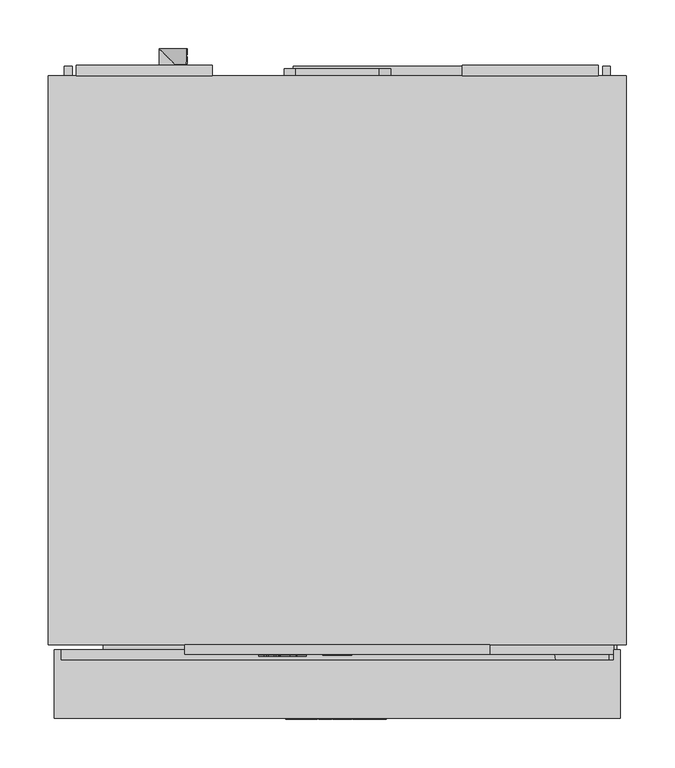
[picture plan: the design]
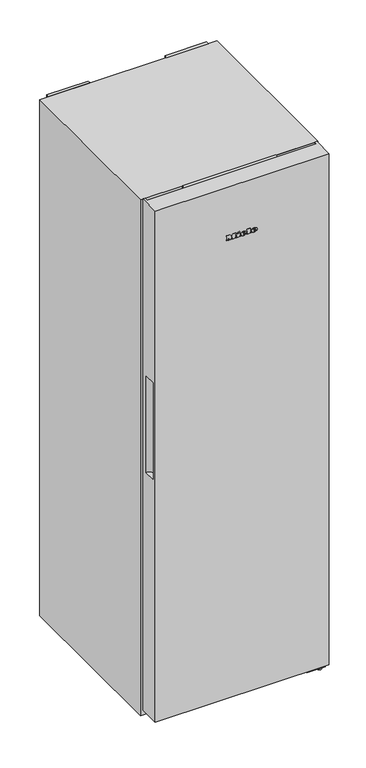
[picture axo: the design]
"""IFC4 building model written with IfcOpenShell, lengths in millimetres: proxy geometry."""

from ifc_helpers import new_model, si_unit, point, frame, frame_2d, origin, origin_with_axes, place, context, project, spatial, polyline, circle_curve, ellipse_curve, trimmed, segment, composite_curve, outline, extrude, faceted_brep, source, transform, mapped, element, save
from ifc_brep_helpers import plane_surface, cylinder_surface, revolved_surface, extruded_surface, advanced_brep


def specialty_equipment_c88ea4fe(model_context):
    return source(origin(), model_context, "Body", "SolidModel", [
        extrude(outline(polyline([(15.0, -609.5), (-15.0, -609.5), (-15.0, -606.5), (15.0, -606.5), (15.0, -609.5)])), frame((0.0, 0.0, 1812.0), z_axis=(0.0, 0.0, 1.0), x_axis=(1.0, 0.0, 0.0)), (0.0, 0.0, 1.0), 28.0),
        extrude(outline(polyline([(1845.5, 105.0), (1845.5, -105.0), (1806.5, -105.0), (1806.5, 105.0), (1845.5, 105.0)]), holes=[polyline([(1840.0, -15.0), (1840.0, 15.0), (1812.0, 15.0), (1812.0, -15.0), (1840.0, -15.0)])]), frame((0.0, -608.5, 0.0), z_axis=(0.0, 1.0, 0.0), x_axis=(0.0, 0.0, 1.0)), (0.0, 0.0, 1.0), 2.0),
        faceted_brep([(157.5, -598.5, 1802.0), (157.5, -608.5, 1802.0), (-157.5, -608.5, 1802.0), (-157.5, -598.5, 1802.0), (157.5, -598.5, 1850.0), (-157.5, -598.5, 1850.0), (-157.5, -608.5, 1850.0), (157.5, -608.5, 1850.0), (-105.0, -608.5, 1845.5), (105.0, -608.5, 1845.5), (105.0, -608.5, 1806.5), (-105.0, -608.5, 1806.5), (105.0, -606.5, 1845.5), (-105.0, -606.5, 1845.5), (-105.0, -606.5, 1806.5), (105.0, -606.5, 1806.5)], [[[0, 1, 2, 3]], [[4, 5, 6, 7]], [[0, 3, 5, 4]], [[3, 2, 6, 5]], [[2, 1, 7, 6], [8, 9, 10, 11]], [[1, 0, 4, 7]], [[12, 13, 14, 15]], [[13, 12, 9, 8]], [[14, 13, 8, 11]], [[15, 14, 11, 10]], [[12, 15, 10, 9]]]),
        advanced_brep(
        [(39.0804776, -675.5, 1668.7956125), (39.0804776, -675.5, 1670.5126125), (50.4534776, -675.5, 1670.5126125), (30.6654776, -675.5, 1670.5126125), (35.3404776, -675.5, 1664.7666125), (50.1644776, -675.5, 1668.7956125), (45.0304776, -675.5, 1668.7956125), (40.9844776, -675.5, 1666.8916125), (39.0804776, -675.5, 1672.6886125), (39.0804776, -675.5, 1674.5416125), (41.9874776, -675.5, 1674.5416125), (41.9874776, -675.5, 1672.6886125), (39.0804776, -674.5, 1668.7956125), (40.9844776, -674.5, 1666.8916125), (45.0304776, -674.5, 1668.7956125), (50.1644776, -674.5, 1668.7956125), (35.3404776, -674.5, 1664.7666125), (30.6654776, -674.5, 1670.5126125), (50.4534776, -674.5, 1670.5126125), (39.0804776, -674.5, 1670.5126125), (39.0804776, -674.5, 1672.6886125), (41.9874776, -674.5, 1672.6886125), (41.9874776, -674.5, 1674.5416125), (39.0804776, -674.5, 1674.5416125)],
        [
            (0, 1),
            (1, 2),
            (2, 3, ellipse_curve(frame((40.5594776, -675.5, 1670.5126125), z_axis=(0.0, -1.0, 0.0), x_axis=(-1.0, 0.0, 0.0)), 9.894, 8.177)),
            (3, 4, circle_curve(frame((37.2445704, -675.5, 1671.0906125), z_axis=(0.0, -1.0, 0.0), x_axis=(0.0, 0.0, -1.0)), 6.6044337)),
            (4, 5, circle_curve(frame((40.361414, -675.5, 1675.5786125), z_axis=(0.0, -1.0, 0.0), x_axis=(0.0, 0.0, -1.0)), 11.9209541)),
            (5, 6),
            (6, 7, circle_curve(frame((41.8154776, -675.5, 1670.3766125), z_axis=(0.0, 1.0, 0.0), x_axis=(0.0, 0.0, -1.0)), 3.5827065)),
            (7, 0, circle_curve(frame((40.9844776, -675.5, 1668.7956125), z_axis=(0.0, 1.0, 0.0), x_axis=(0.0, 0.0, -1.0)), 1.904)),
            (8, 9),
            (9, 10, circle_curve(frame((40.5339776, -675.5, 1674.5416125), z_axis=(0.0, 1.0, 0.0), x_axis=(0.0, 0.0, -1.0)), 1.4535)),
            (10, 11),
            (11, 8),
            (12, 13, circle_curve(frame((40.9844776, -674.5, 1668.7956125), z_axis=(0.0, -1.0, 0.0), x_axis=(0.0, 0.0, -1.0)), 1.904)),
            (13, 14, circle_curve(frame((41.8154776, -674.5, 1670.3766125), z_axis=(0.0, -1.0, 0.0), x_axis=(0.0, 0.0, -1.0)), 3.5827065)),
            (14, 15),
            (15, 16, circle_curve(frame((40.361414, -674.5, 1675.5786125), z_axis=(0.0, 1.0, 0.0), x_axis=(0.0, 0.0, -1.0)), 11.9209541)),
            (16, 17, circle_curve(frame((37.2445704, -674.5, 1671.0906125), z_axis=(0.0, 1.0, 0.0), x_axis=(0.0, 0.0, -1.0)), 6.6044337)),
            (17, 18, ellipse_curve(frame((40.5594776, -674.5, 1670.5126125), z_axis=(0.0, 1.0, 0.0), x_axis=(-1.0, 0.0, 0.0)), 9.894, 8.177)),
            (18, 19),
            (19, 12),
            (20, 21),
            (21, 22),
            (22, 23, circle_curve(frame((40.5339776, -674.5, 1674.5416125), z_axis=(0.0, -1.0, 0.0), x_axis=(0.0, 0.0, -1.0)), 1.4535)),
            (23, 20),
            (0, 12),
            (19, 1),
            (18, 2),
            (5, 15),
            (14, 6),
            (17, 3),
            (13, 7),
            (16, 4),
            (8, 20),
            (23, 9),
            (22, 10),
            (21, 11),
        ],
        [
            plane_surface(frame((39.0804776, -675.5, 1670.5126125), z_axis=(0.0, -1.0, 0.0), x_axis=(0.0, 0.0, 1.0))),
            plane_surface(frame((39.0804776, -674.5, 1670.5126125), z_axis=(0.0, 1.0, 0.0), x_axis=(0.0, 0.0, -1.0))),
            plane_surface(frame((39.0804776, -675.5, 1668.7956125), z_axis=(1.0, 0.0, 0.0), x_axis=(0.0, 1.0, 0.0))),
            plane_surface(frame((39.0804776, -675.5, 1670.5126125), z_axis=(0.0, 0.0, -1.0), x_axis=(0.0, 1.0, 0.0))),
            plane_surface(frame((50.1644776, -675.5, 1668.7956125), z_axis=(0.0, 0.0, 1.0), x_axis=(0.0, 1.0, 0.0))),
            extruded_surface(trimmed(ellipse_curve(frame((40.5594776, -673.5, 1670.5126125), z_axis=(0.0, -1.0, 0.0), x_axis=(-1.0, 0.0, 0.0)), 9.894, 8.177), [point((50.4534776, -673.5, 1670.5126125))], [point((30.6654776, -673.5, 1670.5126125))], True, "CARTESIAN"), (0.0, -1.0, 0.0), 1.0),
            revolved_surface(polyline([(41.8154776, -674.5, 1666.7939059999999), (41.8154776, -675.5, 1666.7939059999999)]), (41.8154776, -674.5, 1670.3766125), (0.0, 1.0, 0.0)),
            revolved_surface(polyline([(40.9844776, -674.5, 1666.8916125), (40.9844776, -675.5, 1666.8916125)]), (40.9844776, -674.5, 1668.7956125), (0.0, 1.0, 0.0)),
            cylinder_surface(frame((37.2445704, -674.5, 1671.0906125), z_axis=(0.0, -1.0, 0.0), x_axis=(0.0, 0.0, -1.0)), 6.6044337),
            cylinder_surface(frame((40.361414, -674.5, 1675.5786125), z_axis=(0.0, -1.0, 0.0), x_axis=(0.0, 0.0, -1.0)), 11.9209541),
            plane_surface(frame((39.0804776, -675.5, 1672.6886125), z_axis=(1.0, 0.0, 0.0), x_axis=(0.0, 1.0, 0.0))),
            revolved_surface(polyline([(40.5339776, -674.5, 1673.0881124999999), (40.5339776, -675.5, 1673.0881124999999)]), (40.5339776, -674.5, 1674.5416125), (0.0, 1.0, 0.0)),
            plane_surface(frame((41.9874776, -675.5, 1674.5416125), z_axis=(-1.0, 0.0, 0.0), x_axis=(0.0, 1.0, 0.0))),
            plane_surface(frame((41.9874776, -675.5, 1672.6886125), z_axis=(0.0, 0.0, 1.0), x_axis=(0.0, 1.0, 0.0))),
        ],
        [
            (0, [[1, 2, 3, 4, 5, 6, 7, 8], [9, 10, 11, 12]]),
            (1, [[13, 14, 15, 16, 17, 18, 19, 20], [21, 22, 23, 24]]),
            (2, [[-1, 25, -20, 26]]),
            (3, [[-2, -26, -19, 27]]),
            (4, [[-6, 28, -15, 29]]),
            (5, [[-3, -27, -18, 30]]),
            (6, [[-7, -29, -14, 31]]),
            (7, [[-8, -31, -13, -25]]),
            (8, [[-4, -30, -17, 32]]),
            (9, [[-5, -32, -16, -28]]),
            (10, [[-9, 33, -24, 34]]),
            (11, [[-10, -34, -23, 35]]),
            (12, [[-11, -35, -22, 36]]),
            (13, [[-12, -36, -21, -33]]),
        ],
    ),
        advanced_brep(
        [(3.6014776, -675.5, 1668.7956125), (3.6014776, -675.5, 1670.5126125), (14.9744776, -675.5, 1670.5126125), (-4.8135224, -675.5, 1670.5126125), (-0.1385224, -675.5, 1664.7666125), (14.6854776, -675.5, 1668.7956125), (9.5514776, -675.5, 1668.7956125), (5.5054776, -675.5, 1666.8916125), (3.6014776, -675.5, 1672.6886125), (3.6014776, -675.5, 1674.5416125), (6.5084776, -675.5, 1674.5416125), (6.5084776, -675.5, 1672.6886125), (3.6014776, -674.5, 1668.7956125), (5.5054776, -674.5, 1666.8916125), (9.5514776, -674.5, 1668.7956125), (14.6854776, -674.5, 1668.7956125), (-0.1385224, -674.5, 1664.7666125), (-4.8135224, -674.5, 1670.5126125), (14.9744776, -674.5, 1670.5126125), (3.6014776, -674.5, 1670.5126125), (3.6014776, -674.5, 1672.6886125), (6.5084776, -674.5, 1672.6886125), (6.5084776, -674.5, 1674.5416125), (3.6014776, -674.5, 1674.5416125)],
        [
            (0, 1),
            (1, 2),
            (2, 3, ellipse_curve(frame((5.0804776, -675.5, 1670.5126125), z_axis=(0.0, -1.0, 0.0), x_axis=(-1.0, 0.0, 0.0)), 9.894, 8.177)),
            (3, 4, circle_curve(frame((1.7655704, -675.5, 1671.0906125), z_axis=(0.0, -1.0, 0.0), x_axis=(0.0, 0.0, -1.0)), 6.6044337)),
            (4, 5, circle_curve(frame((4.882414, -675.5, 1675.5786125), z_axis=(0.0, -1.0, 0.0), x_axis=(0.0, 0.0, -1.0)), 11.9209541)),
            (5, 6),
            (6, 7, circle_curve(frame((6.3364776, -675.5, 1670.3766125), z_axis=(0.0, 1.0, 0.0), x_axis=(0.0, 0.0, -1.0)), 3.5827065)),
            (7, 0, circle_curve(frame((5.5054776, -675.5, 1668.7956125), z_axis=(0.0, 1.0, 0.0), x_axis=(0.0, 0.0, -1.0)), 1.904)),
            (8, 9),
            (9, 10, circle_curve(frame((5.0549776, -675.5, 1674.5416125), z_axis=(0.0, 1.0, 0.0), x_axis=(0.0, 0.0, -1.0)), 1.4535)),
            (10, 11),
            (11, 8),
            (12, 13, circle_curve(frame((5.5054776, -674.5, 1668.7956125), z_axis=(0.0, -1.0, 0.0), x_axis=(0.0, 0.0, -1.0)), 1.904)),
            (13, 14, circle_curve(frame((6.3364776, -674.5, 1670.3766125), z_axis=(0.0, -1.0, 0.0), x_axis=(0.0, 0.0, -1.0)), 3.5827065)),
            (14, 15),
            (15, 16, circle_curve(frame((4.882414, -674.5, 1675.5786125), z_axis=(0.0, 1.0, 0.0), x_axis=(0.0, 0.0, -1.0)), 11.9209541)),
            (16, 17, circle_curve(frame((1.7655704, -674.5, 1671.0906125), z_axis=(0.0, 1.0, 0.0), x_axis=(0.0, 0.0, -1.0)), 6.6044337)),
            (17, 18, ellipse_curve(frame((5.0804776, -674.5, 1670.5126125), z_axis=(0.0, 1.0, 0.0), x_axis=(-1.0, 0.0, 0.0)), 9.894, 8.177)),
            (18, 19),
            (19, 12),
            (20, 21),
            (21, 22),
            (22, 23, circle_curve(frame((5.0549776, -674.5, 1674.5416125), z_axis=(0.0, -1.0, 0.0), x_axis=(0.0, 0.0, -1.0)), 1.4535)),
            (23, 20),
            (0, 12),
            (19, 1),
            (18, 2),
            (5, 15),
            (14, 6),
            (17, 3),
            (13, 7),
            (16, 4),
            (8, 20),
            (23, 9),
            (22, 10),
            (21, 11),
        ],
        [
            plane_surface(frame((3.6014776, -675.5, 1670.5126125), z_axis=(0.0, -1.0, 0.0), x_axis=(0.0, 0.0, 1.0))),
            plane_surface(frame((3.6014776, -674.5, 1670.5126125), z_axis=(0.0, 1.0, 0.0), x_axis=(0.0, 0.0, -1.0))),
            plane_surface(frame((3.6014776, -675.5, 1668.7956125), z_axis=(1.0, 0.0, 0.0), x_axis=(0.0, 1.0, 0.0))),
            plane_surface(frame((3.6014776, -675.5, 1670.5126125), z_axis=(0.0, 0.0, -1.0), x_axis=(0.0, 1.0, 0.0))),
            plane_surface(frame((14.6854776, -675.5, 1668.7956125), z_axis=(0.0, 0.0, 1.0), x_axis=(0.0, 1.0, 0.0))),
            extruded_surface(trimmed(ellipse_curve(frame((5.0804776, -673.5, 1670.5126125), z_axis=(0.0, -1.0, 0.0), x_axis=(-1.0, 0.0, 0.0)), 9.894, 8.177), [point((14.9744776, -673.5, 1670.5126125))], [point((-4.8135224, -673.5, 1670.5126125))], True, "CARTESIAN"), (0.0, -1.0, 0.0), 1.0),
            revolved_surface(polyline([(6.3364776, -674.5, 1666.7939059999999), (6.3364776, -675.5, 1666.7939059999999)]), (6.3364776, -674.5, 1670.3766125), (0.0, 1.0, 0.0)),
            revolved_surface(polyline([(5.5054776, -674.5, 1666.8916125), (5.5054776, -675.5, 1666.8916125)]), (5.5054776, -674.5, 1668.7956125), (0.0, 1.0, 0.0)),
            cylinder_surface(frame((1.7655704, -674.5, 1671.0906125), z_axis=(0.0, -1.0, 0.0), x_axis=(0.0, 0.0, -1.0)), 6.6044337),
            cylinder_surface(frame((4.882414, -674.5, 1675.5786125), z_axis=(0.0, -1.0, 0.0), x_axis=(0.0, 0.0, -1.0)), 11.9209541),
            plane_surface(frame((3.6014776, -675.5, 1672.6886125), z_axis=(1.0, 0.0, 0.0), x_axis=(0.0, 1.0, 0.0))),
            revolved_surface(polyline([(5.0549776, -674.5, 1673.0881124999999), (5.0549776, -675.5, 1673.0881124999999)]), (5.0549776, -674.5, 1674.5416125), (0.0, 1.0, 0.0)),
            plane_surface(frame((6.5084776, -675.5, 1674.5416125), z_axis=(-1.0, 0.0, 0.0), x_axis=(0.0, 1.0, 0.0))),
            plane_surface(frame((6.5084776, -675.5, 1672.6886125), z_axis=(0.0, 0.0, 1.0), x_axis=(0.0, 1.0, 0.0))),
        ],
        [
            (0, [[1, 2, 3, 4, 5, 6, 7, 8], [9, 10, 11, 12]]),
            (1, [[13, 14, 15, 16, 17, 18, 19, 20], [21, 22, 23, 24]]),
            (2, [[-1, 25, -20, 26]]),
            (3, [[-2, -26, -19, 27]]),
            (4, [[-6, 28, -15, 29]]),
            (5, [[-3, -27, -18, 30]]),
            (6, [[-7, -29, -14, 31]]),
            (7, [[-8, -31, -13, -25]]),
            (8, [[-4, -30, -17, 32]]),
            (9, [[-5, -32, -16, -28]]),
            (10, [[-9, 33, -24, 34]]),
            (11, [[-10, -34, -23, 35]]),
            (12, [[-11, -35, -22, 36]]),
            (13, [[-12, -36, -21, -33]]),
        ],
    ),
        extrude(outline(polyline([(1680.7636125, -14.9795224), (1678.0096125, -13.6875224), (1680.6956125, -7.9245224), (1683.4496125, -9.1995224), (1680.7636125, -14.9795224)])), frame((0.0, -675.5, 0.0), z_axis=(0.0, 1.0, 0.0), x_axis=(0.0, 0.0, 1.0)), (0.0, 0.0, 1.0), 1.0),
        extrude(outline(polyline([(1677.6356125, -19.1785224), (1674.5926125, -19.1785224), (1674.5926125, -17.1555224), (1667.6226125, -17.1555224), (1667.6226125, -19.1785224), (1664.7666125, -19.1785224), (1664.7666125, -5.7655224), (1667.6226125, -5.7655224), (1667.6226125, -7.7375224), (1677.6356125, -7.7375224), (1677.6356125, -19.1785224)])), frame((0.0, -675.5, 0.0), z_axis=(0.0, 1.0, 0.0), x_axis=(0.0, 0.0, 1.0)), (0.0, 0.0, 1.0), 1.0),
        extrude(outline(polyline([(1678.9956125, 15.9264776), (1678.9956125, 17.9664776), (1667.6226125, 17.9664776), (1667.6226125, 15.9264776), (1664.7666125, 15.9264776), (1664.7666125, 29.7134776), (1667.6226125, 29.7134776), (1667.6226125, 27.6224776), (1681.7666125, 27.6224776), (1681.7666125, 15.9264776), (1678.9956125, 15.9264776)])), frame((0.0, -675.5, 0.0), z_axis=(0.0, 1.0, 0.0), x_axis=(0.0, 0.0, 1.0)), (0.0, 0.0, 1.0), 1.0),
        extrude(outline(polyline([(1678.9956125, -53.0595224), (1678.9956125, -51.0025224), (1667.6226125, -51.0025224), (1667.6226125, -53.0595224), (1664.7666125, -53.0595224), (1664.7666125, -45.5795224), (1667.6226125, -45.5795224), (1667.6226125, -47.6195224), (1674.7967372, -47.6195224), (1664.7666125, -40.0205224), (1675.2068348, -32.3875224), (1667.6226125, -32.3875224), (1667.6226125, -34.4785224), (1664.7666125, -34.4785224), (1664.7666125, -20.9125224), (1667.6226125, -20.9125224), (1667.6226125, -23.0715224), (1678.9956125, -23.0715224), (1678.9956125, -20.9125224), (1681.7666125, -20.9125224), (1681.7666125, -31.2655224), (1675.3916125, -36.2295224), (1681.7666125, -41.2105224), (1681.7666125, -53.0595224), (1678.9956125, -53.0595224)])), frame((0.0, -675.5, 0.0), z_axis=(0.0, 1.0, 0.0), x_axis=(0.0, 0.0, 1.0)), (0.0, 0.0, 1.0), 1.0),
        advanced_brep(
        [(-37.64, -610.5, 1828.896), (-37.64, -610.5, 1829.704), (-32.288, -610.5, 1829.704), (-41.6, -610.5, 1829.704), (-39.4, -610.5, 1827.0), (-32.424, -610.5, 1828.896), (-34.84, -610.5, 1828.896), (-36.744, -610.5, 1828.0), (-37.64, -610.5, 1830.728), (-37.64, -610.5, 1831.6), (-36.272, -610.5, 1831.6), (-36.272, -610.5, 1830.728), (-37.64, -609.5, 1828.896), (-36.744, -609.5, 1828.0), (-34.84, -609.5, 1828.896), (-32.424, -609.5, 1828.896), (-39.4, -609.5, 1827.0), (-41.6, -609.5, 1829.704), (-32.288, -609.5, 1829.704), (-37.64, -609.5, 1829.704), (-37.64, -609.5, 1830.728), (-36.272, -609.5, 1830.728), (-36.272, -609.5, 1831.6), (-37.64, -609.5, 1831.6)],
        [
            (0, 1),
            (1, 2),
            (2, 3, ellipse_curve(frame((-36.944, -610.5, 1829.704), z_axis=(0.0, -1.0, 0.0), x_axis=(-1.0, 0.0, 0.0)), 4.656, 3.848)),
            (3, 4, circle_curve(frame((-38.5039564, -610.5, 1829.976), z_axis=(0.0, -1.0, 0.0), x_axis=(0.0, 0.0, -1.0)), 3.1079688)),
            (4, 5, circle_curve(frame((-37.0372064, -610.5, 1832.088), z_axis=(0.0, -1.0, 0.0), x_axis=(0.0, 0.0, -1.0)), 5.6098607)),
            (5, 6),
            (6, 7, circle_curve(frame((-36.3529412, -610.5, 1829.64), z_axis=(0.0, 1.0, 0.0), x_axis=(0.0, 0.0, -1.0)), 1.6859795)),
            (7, 0, circle_curve(frame((-36.744, -610.5, 1828.896), z_axis=(0.0, 1.0, 0.0), x_axis=(0.0, 0.0, -1.0)), 0.896)),
            (8, 9),
            (9, 10, circle_curve(frame((-36.956, -610.5, 1831.6), z_axis=(0.0, 1.0, 0.0), x_axis=(0.0, 0.0, -1.0)), 0.684)),
            (10, 11),
            (11, 8),
            (12, 13, circle_curve(frame((-36.744, -609.5, 1828.896), z_axis=(0.0, -1.0, 0.0), x_axis=(0.0, 0.0, -1.0)), 0.896)),
            (13, 14, circle_curve(frame((-36.3529412, -609.5, 1829.64), z_axis=(0.0, -1.0, 0.0), x_axis=(0.0, 0.0, -1.0)), 1.6859795)),
            (14, 15),
            (15, 16, circle_curve(frame((-37.0372064, -609.5, 1832.088), z_axis=(0.0, 1.0, 0.0), x_axis=(0.0, 0.0, -1.0)), 5.6098607)),
            (16, 17, circle_curve(frame((-38.5039564, -609.5, 1829.976), z_axis=(0.0, 1.0, 0.0), x_axis=(0.0, 0.0, -1.0)), 3.1079688)),
            (17, 18, ellipse_curve(frame((-36.944, -609.5, 1829.704), z_axis=(0.0, 1.0, 0.0), x_axis=(-1.0, 0.0, 0.0)), 4.656, 3.848)),
            (18, 19),
            (19, 12),
            (20, 21),
            (21, 22),
            (22, 23, circle_curve(frame((-36.956, -609.5, 1831.6), z_axis=(0.0, -1.0, 0.0), x_axis=(0.0, 0.0, -1.0)), 0.684)),
            (23, 20),
            (0, 12),
            (19, 1),
            (18, 2),
            (5, 15),
            (14, 6),
            (17, 3),
            (13, 7),
            (16, 4),
            (8, 20),
            (23, 9),
            (22, 10),
            (21, 11),
        ],
        [
            plane_surface(frame((-37.64, -610.5, 1829.704), z_axis=(0.0, -1.0, 0.0), x_axis=(0.0, 0.0, 1.0))),
            plane_surface(frame((-37.64, -609.5, 1829.704), z_axis=(0.0, 1.0, 0.0), x_axis=(0.0, 0.0, -1.0))),
            plane_surface(frame((-37.64, -610.5, 1828.896), z_axis=(1.0, 0.0, 0.0), x_axis=(0.0, 1.0, 0.0))),
            plane_surface(frame((-37.64, -610.5, 1829.704), z_axis=(0.0, 0.0, -1.0), x_axis=(0.0, 1.0, 0.0))),
            plane_surface(frame((-32.424, -610.5, 1828.896), z_axis=(0.0, 0.0, 1.0), x_axis=(0.0, 1.0, 0.0))),
            extruded_surface(trimmed(ellipse_curve(frame((-36.944, -608.5, 1829.704), z_axis=(0.0, -1.0, 0.0), x_axis=(-1.0, 0.0, 0.0)), 4.656, 3.848), [point((-32.288, -608.5, 1829.704))], [point((-41.6, -608.5, 1829.704))], True, "CARTESIAN"), (0.0, -1.0, 0.0), 1.0),
            revolved_surface(polyline([(-36.3529412, -609.5, 1827.9540205), (-36.3529412, -610.5, 1827.9540205)]), (-36.3529412, -609.5, 1829.64), (0.0, 1.0, 0.0)),
            revolved_surface(polyline([(-36.744, -609.5, 1828.0), (-36.744, -610.5, 1828.0)]), (-36.744, -609.5, 1828.896), (0.0, 1.0, 0.0)),
            cylinder_surface(frame((-38.5039564, -609.5, 1829.976), z_axis=(0.0, -1.0, 0.0), x_axis=(0.0, 0.0, -1.0)), 3.1079688),
            cylinder_surface(frame((-37.0372064, -609.5, 1832.088), z_axis=(0.0, -1.0, 0.0), x_axis=(0.0, 0.0, -1.0)), 5.6098607),
            plane_surface(frame((-37.64, -610.5, 1830.728), z_axis=(1.0, 0.0, 0.0), x_axis=(0.0, 1.0, 0.0))),
            revolved_surface(polyline([(-36.956, -609.5, 1830.916), (-36.956, -610.5, 1830.916)]), (-36.956, -609.5, 1831.6), (0.0, 1.0, 0.0)),
            plane_surface(frame((-36.272, -610.5, 1831.6), z_axis=(-1.0, 0.0, 0.0), x_axis=(0.0, 1.0, 0.0))),
            plane_surface(frame((-36.272, -610.5, 1830.728), z_axis=(0.0, 0.0, 1.0), x_axis=(0.0, 1.0, 0.0))),
        ],
        [
            (0, [[1, 2, 3, 4, 5, 6, 7, 8], [9, 10, 11, 12]]),
            (1, [[13, 14, 15, 16, 17, 18, 19, 20], [21, 22, 23, 24]]),
            (2, [[-1, 25, -20, 26]]),
            (3, [[-2, -26, -19, 27]]),
            (4, [[-6, 28, -15, 29]]),
            (5, [[-3, -27, -18, 30]]),
            (6, [[-7, -29, -14, 31]]),
            (7, [[-8, -31, -13, -25]]),
            (8, [[-4, -30, -17, 32]]),
            (9, [[-5, -32, -16, -28]]),
            (10, [[-9, 33, -24, 34]]),
            (11, [[-10, -34, -23, 35]]),
            (12, [[-11, -35, -22, 36]]),
            (13, [[-12, -36, -21, -33]]),
        ],
    ),
        advanced_brep(
        [(-54.336, -610.5, 1828.896), (-54.336, -610.5, 1829.704), (-48.984, -610.5, 1829.704), (-58.296, -610.5, 1829.704), (-56.096, -610.5, 1827.0), (-49.12, -610.5, 1828.896), (-51.536, -610.5, 1828.896), (-53.44, -610.5, 1828.0), (-54.336, -610.5, 1830.728), (-54.336, -610.5, 1831.6), (-52.968, -610.5, 1831.6), (-52.968, -610.5, 1830.728), (-54.336, -609.5, 1828.896), (-53.44, -609.5, 1828.0), (-51.536, -609.5, 1828.896), (-49.12, -609.5, 1828.896), (-56.096, -609.5, 1827.0), (-58.296, -609.5, 1829.704), (-48.984, -609.5, 1829.704), (-54.336, -609.5, 1829.704), (-54.336, -609.5, 1830.728), (-52.968, -609.5, 1830.728), (-52.968, -609.5, 1831.6), (-54.336, -609.5, 1831.6)],
        [
            (0, 1),
            (1, 2),
            (2, 3, ellipse_curve(frame((-53.64, -610.5, 1829.704), z_axis=(0.0, -1.0, 0.0), x_axis=(-1.0, 0.0, 0.0)), 4.656, 3.848)),
            (3, 4, circle_curve(frame((-55.1999564, -610.5, 1829.976), z_axis=(0.0, -1.0, 0.0), x_axis=(0.0, 0.0, -1.0)), 3.1079688)),
            (4, 5, circle_curve(frame((-53.7332064, -610.5, 1832.088), z_axis=(0.0, -1.0, 0.0), x_axis=(0.0, 0.0, -1.0)), 5.6098607)),
            (5, 6),
            (6, 7, circle_curve(frame((-53.0489412, -610.5, 1829.64), z_axis=(0.0, 1.0, 0.0), x_axis=(0.0, 0.0, -1.0)), 1.6859795)),
            (7, 0, circle_curve(frame((-53.44, -610.5, 1828.896), z_axis=(0.0, 1.0, 0.0), x_axis=(0.0, 0.0, -1.0)), 0.896)),
            (8, 9),
            (9, 10, circle_curve(frame((-53.652, -610.5, 1831.6), z_axis=(0.0, 1.0, 0.0), x_axis=(0.0, 0.0, -1.0)), 0.684)),
            (10, 11),
            (11, 8),
            (12, 13, circle_curve(frame((-53.44, -609.5, 1828.896), z_axis=(0.0, -1.0, 0.0), x_axis=(0.0, 0.0, -1.0)), 0.896)),
            (13, 14, circle_curve(frame((-53.0489412, -609.5, 1829.64), z_axis=(0.0, -1.0, 0.0), x_axis=(0.0, 0.0, -1.0)), 1.6859795)),
            (14, 15),
            (15, 16, circle_curve(frame((-53.7332064, -609.5, 1832.088), z_axis=(0.0, 1.0, 0.0), x_axis=(0.0, 0.0, -1.0)), 5.6098607)),
            (16, 17, circle_curve(frame((-55.1999564, -609.5, 1829.976), z_axis=(0.0, 1.0, 0.0), x_axis=(0.0, 0.0, -1.0)), 3.1079688)),
            (17, 18, ellipse_curve(frame((-53.64, -609.5, 1829.704), z_axis=(0.0, 1.0, 0.0), x_axis=(-1.0, 0.0, 0.0)), 4.656, 3.848)),
            (18, 19),
            (19, 12),
            (20, 21),
            (21, 22),
            (22, 23, circle_curve(frame((-53.652, -609.5, 1831.6), z_axis=(0.0, -1.0, 0.0), x_axis=(0.0, 0.0, -1.0)), 0.684)),
            (23, 20),
            (0, 12),
            (19, 1),
            (18, 2),
            (5, 15),
            (14, 6),
            (17, 3),
            (13, 7),
            (16, 4),
            (8, 20),
            (23, 9),
            (22, 10),
            (21, 11),
        ],
        [
            plane_surface(frame((-54.336, -610.5, 1829.704), z_axis=(0.0, -1.0, 0.0), x_axis=(0.0, 0.0, 1.0))),
            plane_surface(frame((-54.336, -609.5, 1829.704), z_axis=(0.0, 1.0, 0.0), x_axis=(0.0, 0.0, -1.0))),
            plane_surface(frame((-54.336, -610.5, 1828.896), z_axis=(1.0, 0.0, 0.0), x_axis=(0.0, 1.0, 0.0))),
            plane_surface(frame((-54.336, -610.5, 1829.704), z_axis=(0.0, 0.0, -1.0), x_axis=(0.0, 1.0, 0.0))),
            plane_surface(frame((-49.12, -610.5, 1828.896), z_axis=(0.0, 0.0, 1.0), x_axis=(0.0, 1.0, 0.0))),
            extruded_surface(trimmed(ellipse_curve(frame((-53.64, -608.5, 1829.704), z_axis=(0.0, -1.0, 0.0), x_axis=(-1.0, 0.0, 0.0)), 4.656, 3.848), [point((-48.984, -608.5, 1829.704))], [point((-58.296, -608.5, 1829.704))], True, "CARTESIAN"), (0.0, -1.0, 0.0), 1.0),
            revolved_surface(polyline([(-53.0489412, -609.5, 1827.9540205), (-53.0489412, -610.5, 1827.9540205)]), (-53.0489412, -609.5, 1829.64), (0.0, 1.0, 0.0)),
            revolved_surface(polyline([(-53.44, -609.5, 1828.0), (-53.44, -610.5, 1828.0)]), (-53.44, -609.5, 1828.896), (0.0, 1.0, 0.0)),
            cylinder_surface(frame((-55.1999564, -609.5, 1829.976), z_axis=(0.0, -1.0, 0.0), x_axis=(0.0, 0.0, -1.0)), 3.1079688),
            cylinder_surface(frame((-53.7332064, -609.5, 1832.088), z_axis=(0.0, -1.0, 0.0), x_axis=(0.0, 0.0, -1.0)), 5.6098607),
            plane_surface(frame((-54.336, -610.5, 1830.728), z_axis=(1.0, 0.0, 0.0), x_axis=(0.0, 1.0, 0.0))),
            revolved_surface(polyline([(-53.652, -609.5, 1830.916), (-53.652, -610.5, 1830.916)]), (-53.652, -609.5, 1831.6), (0.0, 1.0, 0.0)),
            plane_surface(frame((-52.968, -610.5, 1831.6), z_axis=(-1.0, 0.0, 0.0), x_axis=(0.0, 1.0, 0.0))),
            plane_surface(frame((-52.968, -610.5, 1830.728), z_axis=(0.0, 0.0, 1.0), x_axis=(0.0, 1.0, 0.0))),
        ],
        [
            (0, [[1, 2, 3, 4, 5, 6, 7, 8], [9, 10, 11, 12]]),
            (1, [[13, 14, 15, 16, 17, 18, 19, 20], [21, 22, 23, 24]]),
            (2, [[-1, 25, -20, 26]]),
            (3, [[-2, -26, -19, 27]]),
            (4, [[-6, 28, -15, 29]]),
            (5, [[-3, -27, -18, 30]]),
            (6, [[-7, -29, -14, 31]]),
            (7, [[-8, -31, -13, -25]]),
            (8, [[-4, -30, -17, 32]]),
            (9, [[-5, -32, -16, -28]]),
            (10, [[-9, 33, -24, 34]]),
            (11, [[-10, -34, -23, 35]]),
            (12, [[-11, -35, -22, 36]]),
            (13, [[-12, -36, -21, -33]]),
        ],
    ),
        extrude(outline(polyline([(1834.528, -63.08), (1833.232, -62.472), (1834.496, -59.76), (1835.792, -60.36), (1834.528, -63.08)])), frame((0.0, -610.5, 0.0), z_axis=(0.0, 1.0, 0.0), x_axis=(0.0, 0.0, 1.0)), (0.0, 0.0, 1.0), 1.0),
        extrude(outline(polyline([(1833.056, -65.056), (1831.624, -65.056), (1831.624, -64.104), (1828.344, -64.104), (1828.344, -65.056), (1827.0, -65.056), (1827.0, -58.744), (1828.344, -58.744), (1828.344, -59.672), (1833.056, -59.672), (1833.056, -65.056)])), frame((0.0, -610.5, 0.0), z_axis=(0.0, 1.0, 0.0), x_axis=(0.0, 0.0, 1.0)), (0.0, 0.0, 1.0), 1.0),
        extrude(outline(polyline([(1833.696, -48.536), (1833.696, -47.576), (1828.344, -47.576), (1828.344, -48.536), (1827.0, -48.536), (1827.0, -42.048), (1828.344, -42.048), (1828.344, -43.032), (1835.0, -43.032), (1835.0, -48.536), (1833.696, -48.536)])), frame((0.0, -610.5, 0.0), z_axis=(0.0, 1.0, 0.0), x_axis=(0.0, 0.0, 1.0)), (0.0, 0.0, 1.0), 1.0),
        extrude(outline(polyline([(1833.696, -81.0), (1833.696, -80.032), (1828.344, -80.032), (1828.344, -81.0), (1827.0, -81.0), (1827.0, -77.48), (1828.344, -77.48), (1828.344, -78.44), (1831.7471247, -78.44), (1827.0, -74.864), (1831.8152223, -71.272), (1828.344, -71.272), (1828.344, -72.256), (1827.0, -72.256), (1827.0, -65.872), (1828.344, -65.872), (1828.344, -66.888), (1833.696, -66.888), (1833.696, -65.872), (1835.0, -65.872), (1835.0, -70.744), (1832.0, -73.08), (1835.0, -75.424), (1835.0, -81.0), (1833.696, -81.0)])), frame((0.0, -610.5, 0.0), z_axis=(0.0, 1.0, 0.0), x_axis=(0.0, 0.0, 1.0)), (0.0, 0.0, 1.0), 1.0),
        extrude(outline(polyline([(-42.8527823, 0.0), (-48.1304417, 3.2708192), (-29.8908031, 3.2708192), (-34.9274229, 0.0), (-42.8527823, 0.0)])), frame((238.5469678, 0.0, 0.0), z_axis=(1.0, 0.0, 0.0), x_axis=(0.0, 1.0, 0.0)), (0.0, 0.0, 1.0), 15.1632647),
        extrude(outline(polyline([(-42.8527823, 0.0), (-48.1304417, 3.2708192), (-29.8908031, 3.2708192), (-34.9274229, 0.0), (-42.8527823, 0.0)])), frame((-253.7102325, 0.0, 0.0), z_axis=(1.0, 0.0, 0.0), x_axis=(0.0, 1.0, 0.0)), (0.0, 0.0, 1.0), 15.1632647),
        extrude(outline(polyline([(2.1227397, 65.0), (2.1227397, 75.045631), (9.343037, 75.045631), (9.343037, 73.7899271), (3.3784436, 73.7899271), (3.3784436, 70.8076304), (9.029111, 70.8076304), (9.029111, 69.5519266), (3.3784436, 69.5519266), (3.3784436, 66.2557039), (9.5, 66.2557039), (9.5, 65.0), (2.1227397, 65.0)])), frame((-156.0615355, 0.0, 0.0), z_axis=(1.0, 0.0, 0.0), x_axis=(0.0, 1.0, 0.0)), (0.0, 0.0, 1.0), 1.0),
        extrude(outline(polyline([(11.3835558, 65.0), (11.3835558, 75.045631), (12.6392597, 75.045631), (12.6392597, 66.2557039), (17.6620752, 66.2557039), (17.6620752, 65.0), (11.3835558, 65.0)])), frame((-156.0615355, 0.0, 0.0), z_axis=(1.0, 0.0, 0.0), x_axis=(0.0, 1.0, 0.0)), (0.0, 0.0, 1.0), 1.0),
        advanced_brep(
        [(-168.0615355, -10.5, 70.0), (-184.0615355, -10.5, 70.0), (-168.0615355, 1.5, 70.0), (-184.0615355, 17.5, 70.0), (-156.0615355, 1.5, 70.0), (-156.0615355, 17.5, 70.0)],
        [
            (0, 1, circle_curve(frame((-176.0615355, -10.5, 70.0), z_axis=(0.0, -1.0, 0.0), x_axis=(-1.0, 0.0, 0.0)), 8.0)),
            (1, 0, circle_curve(frame((-176.0615355, -10.5, 70.0), z_axis=(0.0, -1.0, 0.0), x_axis=(-1.0, 0.0, 0.0)), 8.0)),
            (0, 2),
            (2, 3, ellipse_curve(frame((-176.0615355, 9.5, 70.0), z_axis=(-0.7071067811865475, -0.7071067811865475, 0.0), x_axis=(0.7071067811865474, -0.7071067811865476, 0.0)), 11.3137085, 8.0)),
            (3, 1),
            (3, 2, ellipse_curve(frame((-176.0615355, 9.5, 70.0), z_axis=(-0.7071067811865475, -0.7071067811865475, 0.0), x_axis=(0.7071067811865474, -0.7071067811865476, 0.0)), 11.3137085, 8.0)),
            (4, 5, circle_curve(frame((-156.0615355, 9.5, 70.0), z_axis=(1.0, 0.0, 0.0), x_axis=(0.0, 1.0, 0.0)), 8.0)),
            (5, 4, circle_curve(frame((-156.0615355, 9.5, 70.0), z_axis=(1.0, 0.0, 0.0), x_axis=(0.0, 1.0, 0.0)), 8.0)),
            (2, 4),
            (5, 3),
        ],
        [
            plane_surface(frame((-176.0615355, -10.5, 0.0), z_axis=(0.0, -1.0, 0.0), x_axis=(0.0, 0.0, 1.0))),
            cylinder_surface(frame((-176.0615355, -10.5, 70.0), z_axis=(0.0, -1.0, 0.0), x_axis=(-1.0, 0.0, 0.0)), 8.0),
            plane_surface(frame((-156.0615355, 9.5, 0.0), z_axis=(1.0, 0.0, 0.0), x_axis=(0.0, 0.0, 1.0))),
            cylinder_surface(frame((-176.0615355, 9.5, 70.0), z_axis=(-1.0, 0.0, 0.0), x_axis=(0.0, 1.0, 0.0)), 8.0),
        ],
        [
            (0, [[1, 2]]),
            (1, [[-1, 3, 4, 5]]),
            (1, [[-2, -5, 6, -3]]),
            (2, [[7, 8]]),
            (3, [[-4, 9, -8, 10]]),
            (3, [[-6, -10, -7, -9]]),
        ],
    ),
        extrude(outline(polyline([(-118.9841834, 15.0), (-62.9841834, 15.0), (-75.5706779, 0.0), (-106.3976889, 0.0), (-118.9841834, 15.0)])), frame((-288.5, 0.0, 0.0), z_axis=(1.0, 0.0, 0.0), x_axis=(0.0, 1.0, 0.0)), (0.0, 0.0, 1.0), 16.0),
        extrude(outline(polyline([(-118.9841834, 15.0), (-62.9841834, 15.0), (-75.5706779, 0.0), (-106.3976889, 0.0), (-118.9841834, 15.0)])), frame((272.5, 0.0, 0.0), z_axis=(1.0, 0.0, 0.0), x_axis=(0.0, 1.0, 0.0)), (0.0, 0.0, 1.0), 16.0),
        extrude(outline(polyline([(281.8051758, -10.5), (274.2947998, -10.5), (274.2947998, -0.5), (281.8051758, -0.5), (281.8051758, -10.5)])), frame((0.0, 0.0, 239.4947815), z_axis=(0.0, 0.0, 1.0), x_axis=(1.0, 0.0, 0.0)), (0.0, 0.0, 1.0), 18.4103699),
        extrude(outline(polyline([(-274.0827332, -10.5), (-282.1051331, -10.5), (-282.1051331, -0.5), (-274.0827332, -0.5), (-274.0827332, -10.5)])), frame((0.0, 0.0, 239.4947815), z_axis=(0.0, 0.0, 1.0), x_axis=(1.0, 0.0, 0.0)), (0.0, 0.0, 1.0), 18.3224792),
        extrude(outline(polyline([(190.0, 177.5), (133.0, 177.5), (133.0, -45.5), (64.0, -45.5), (64.0, 258.5), (190.0, 258.5), (190.0, 177.5)])), frame((0.0, -10.5, 0.0), z_axis=(0.0, 1.0, 0.0), x_axis=(0.0, 0.0, 1.0)), (0.0, 0.0, 1.0), 10.0),
        extrude(outline(polyline([(269.5372046, -10.5), (129.0, -10.5), (129.0, 0.0), (269.5372046, 0.0), (269.5372046, -10.5)])), frame((0.0, 0.0, 1826.0), z_axis=(0.0, 0.0, 1.0), x_axis=(1.0, 0.0, 0.0)), (0.0, 0.0, 1.0), 24.0),
        extrude(outline(polyline([(-129.0, -10.5), (-269.5372046, -10.5), (-269.5372046, 0.0), (-129.0, 0.0), (-129.0, -10.5)])), frame((0.0, 0.0, 1826.0), z_axis=(0.0, 0.0, 1.0), x_axis=(1.0, 0.0, 0.0)), (0.0, 0.0, 1.0), 24.0),
        extrude(outline(polyline([(64.0, -159.5), (-64.0, -159.5), (-64.0, -71.5), (64.0, -71.5), (64.0, -159.5)])), frame((0.0, 0.0, 1636.0), z_axis=(0.0, 0.0, 1.0), x_axis=(1.0, 0.0, 0.0)), (0.0, 0.0, 1.0), 177.6535004),
        extrude(outline(polyline([(55.0, -521.5), (55.0, -575.5), (-55.0, -575.5), (-55.0, -521.5), (55.0, -521.5)])), frame((0.0, 0.0, 1759.0), z_axis=(0.0, 0.0, 1.0), x_axis=(1.0, 0.0, 0.0)), (0.0, 0.0, 1.0), 1.0),
        extrude(outline(composite_curve([segment(trimmed(circle_curve(frame_2d((-248.75, -584.5)), 10.0), [point((-258.75, -584.5))], [point((-238.75, -584.5))], False, "CARTESIAN"), True, "CONTINUOUS"), segment(trimmed(circle_curve(frame_2d((-248.75, -584.5)), 10.0), [point((-238.75, -584.5))], [point((-258.75, -584.5))], False, "CARTESIAN"), True, "CONTINUOUS")], self_intersect=False)), origin_with_axes(), (0.0, 0.0, 1.0), 15.0),
        extrude(outline(composite_curve([segment(trimmed(circle_curve(frame_2d((248.75, -584.4761218)), 10.0), [point((238.75, -584.4761218))], [point((258.75, -584.4761218))], False, "CARTESIAN"), True, "CONTINUOUS"), segment(trimmed(circle_curve(frame_2d((248.75, -584.4761218)), 10.0), [point((258.75, -584.4761218))], [point((238.75, -584.4761218))], False, "CARTESIAN"), True, "CONTINUOUS")], self_intersect=False)), origin_with_axes(), (0.0, 0.0, 1.0), 15.0),
        extrude(outline(polyline([(240.0, -290.5), (-240.0, -290.5), (-240.0, -71.5), (240.0, -71.5), (240.0, -290.5)])), frame((0.0, 0.0, 129.0), z_axis=(0.0, 0.0, 1.0), x_axis=(1.0, 0.0, 0.0)), (0.0, 0.0, 1.0), 190.0),
        extrude(outline(composite_curve([segment(trimmed(circle_curve(frame_2d((1162.0, -43.0)), 12.0), [point((1174.0, -43.0))], [point((1162.0, -55.0))], False, "CARTESIAN"), True, "CONTINUOUS"), segment(polyline([(1162.0, -55.0), (1138.0, -55.0)]), True, "CONTINUOUS"), segment(trimmed(circle_curve(frame_2d((1138.0, -43.0)), 12.0), [point((1138.0, -55.0))], [point((1126.0, -43.0))], False, "CARTESIAN"), True, "CONTINUOUS"), segment(polyline([(1126.0, -43.0), (1126.0, 43.0)]), True, "CONTINUOUS"), segment(trimmed(circle_curve(frame_2d((1138.0, 43.0)), 12.0), [point((1126.0, 43.0))], [point((1138.0, 55.0))], False, "CARTESIAN"), True, "CONTINUOUS"), segment(polyline([(1138.0, 55.0), (1162.0, 55.0)]), True, "CONTINUOUS"), segment(trimmed(circle_curve(frame_2d((1162.0, 43.0)), 12.0), [point((1162.0, 55.0))], [point((1174.0, 43.0))], False, "CARTESIAN"), True, "CONTINUOUS"), segment(polyline([(1174.0, 43.0), (1174.0, -43.0)]), True, "CONTINUOUS")], self_intersect=False)), frame((0.0, -10.5, 0.0), z_axis=(0.0, 1.0, 0.0), x_axis=(0.0, 0.0, 1.0)), (0.0, 0.0, 1.0), 7.0),
        extrude(outline(polyline([(272.5, -28.6436023), (272.5, -529.6387407), (-272.5, -529.6387407), (-272.5, -28.6436023), (272.5, -28.6436023)])), frame((0.0, 0.0, 3.2708192), z_axis=(0.0, 0.0, 1.0), x_axis=(1.0, 0.0, 0.0)), (0.0, 0.0, 1.0), 11.7291808),
        faceted_brep([(298.5, -10.5, 1850.0), (-298.5, -10.5, 1850.0), (-298.5, -598.5, 1850.0), (298.5, -598.5, 1850.0), (298.5, -10.5, 15.0), (298.5, -598.5, 15.0), (-298.5, -598.5, 15.0), (-298.5, -10.5, 15.0), (-240.0, -598.5, 1760.0), (240.0, -598.5, 1760.0), (240.0, -598.5, 129.0), (-240.0, -598.5, 129.0), (-240.0, -468.5, 1760.0), (240.0, -468.5, 1760.0), (240.0, -71.5, 129.0), (-240.0, -71.5, 129.0), (240.0, -71.5, 1813.6535004), (-240.0, -71.5, 1813.6535004), (-240.0, -468.5, 1813.6535004), (240.0, -468.5, 1813.6535004)], [[[0, 1, 2, 3]], [[4, 5, 6, 7]], [[1, 0, 4, 7]], [[2, 1, 7, 6]], [[3, 2, 6, 5], [8, 9, 10, 11]], [[0, 3, 5, 4]], [[9, 8, 12, 13]], [[14, 15, 11, 10]], [[15, 14, 16, 17]], [[15, 17, 18, 12, 8, 11]], [[16, 14, 10, 9, 13, 19]], [[19, 18, 17, 16]], [[18, 19, 13, 12]]]),
        extrude(outline(composite_curve([segment(trimmed(circle_curve(frame_2d((276.9539666, -644.7854989)), 7.0), [point((269.9539666, -644.7854989))], [point((283.9539666, -644.7854989))], False, "CARTESIAN"), True, "CONTINUOUS"), segment(trimmed(circle_curve(frame_2d((276.9539666, -644.7854989)), 7.0), [point((283.9539666, -644.7854989))], [point((269.9539666, -644.7854989))], False, "CARTESIAN"), True, "CONTINUOUS")], self_intersect=False)), frame((0.0, 0.0, 10.0), z_axis=(0.0, 0.0, 1.0), x_axis=(1.0, 0.0, 0.0)), (0.0, 0.0, 1.0), 11.0),
        extrude(outline(polyline([(291.8779467, -660.5), (227.8680756, -660.5), (227.8680756, -603.5), (291.8779467, -603.5), (291.8779467, -660.5)])), frame((0.0, 0.0, 31.5014777), z_axis=(0.0, 0.0, 1.0), x_axis=(1.0, 0.0, 0.0)), (0.0, 0.0, 1.0), 4.4985223),
        extrude(outline(composite_curve([segment(trimmed(circle_curve(frame_2d((274.5, -642.5)), 10.0), [point((264.5, -642.5))], [point((284.5, -642.5))], False, "CARTESIAN"), True, "CONTINUOUS"), segment(trimmed(circle_curve(frame_2d((274.5, -642.5)), 10.0), [point((284.5, -642.5))], [point((264.5, -642.5))], False, "CARTESIAN"), True, "CONTINUOUS")], self_intersect=False)), frame((0.0, 0.0, 27.0014777), z_axis=(0.0, 0.0, 1.0), x_axis=(1.0, 0.0, 0.0)), (0.0, 0.0, 1.0), 4.5),
        extrude(outline(polyline([(242.0, -603.5), (-242.0, -603.5), (-242.0, -598.5), (242.0, -598.5), (242.0, -603.5)])), frame((0.0, 0.0, 128.0014777), z_axis=(0.0, 0.0, 1.0), x_axis=(1.0, 0.0, 0.0)), (0.0, 0.0, 1.0), 1639.0),
        extrude(outline(polyline([(233.3907627, -657.6644264), (224.7217479, -608.5), (280.684623, -608.5), (282.5, -657.6644264), (233.3907627, -657.6644264)])), frame((0.0, 0.0, 1817.6745089), z_axis=(0.0, 0.0, 1.0), x_axis=(1.0, 0.0, 0.0)), (0.0, 0.0, 1.0), 23.7898602),
        extrude(outline(polyline([(285.5, -608.5), (157.5, -608.5), (157.5, -598.5), (285.5, -598.5), (285.5, -608.5)])), frame((0.0, 0.0, 1800.5014777), z_axis=(0.0, 0.0, 1.0), x_axis=(1.0, 0.0, 0.0)), (0.0, 0.0, 1.0), 48.0),
        extrude(outline(polyline([(-598.5, 21.0), (-660.5, 21.0), (-660.5, 27.0014777), (-603.5, 27.0014777), (-603.5, 69.0014777), (-598.5, 69.0014777), (-598.5, 21.0)])), frame((226.5, 0.0, 0.0), z_axis=(1.0, 0.0, 0.0), x_axis=(0.0, 1.0, 0.0)), (0.0, 0.0, 1.0), 62.0),
        advanced_brep(
        [(292.5, -674.5, 1854.0), (-292.5, -674.5, 1854.0), (-292.5, -674.5, 36.0), (292.5, -674.5, 36.0), (292.5, -603.5, 1854.0), (292.5, -603.5, 36.0), (222.5, -603.5, 36.0), (222.5, -603.5, 66.0), (-222.5, -603.5, 66.0), (-222.5, -603.5, 36.0), (-292.5, -603.5, 36.0), (-292.5, -603.5, 1854.0), (-285.5, -603.5, 1854.0), (-285.5, -603.5, 1797.0), (285.5, -603.5, 1797.0), (285.5, -603.5, 1854.0), (285.5, -614.5, 1854.0), (-285.5, -614.5, 1854.0), (-292.5, -660.2074562, 891.0), (-292.5, -620.2074562, 891.0), (-292.5, -620.2074562, 1234.0), (-292.5, -660.2074562, 1234.0), (-222.5, -645.4397305, 36.0), (222.5, -645.4397305, 36.0), (222.5, -617.5, 66.0), (-222.5, -617.5, 66.0), (285.5, -614.5, 1797.0), (-285.5, -614.5, 1797.0), (285.5, -614.5, 1848.5014777), (192.5, -614.5, 1848.5014777), (192.5, -614.5, 1800.5014777), (285.5, -614.5, 1800.5014777), (192.5, -660.3426016, 1848.5014777), (285.5, -660.3426016, 1848.5014777), (285.5, -660.3426016, 1800.5014777), (192.5, -660.3426016, 1800.5014777), (-272.5, -640.2074562, 891.0), (-272.5, -640.2074562, 1234.0)],
        [
            (0, 1),
            (1, 2),
            (2, 3),
            (3, 0),
            (4, 5),
            (5, 6),
            (6, 7),
            (7, 8),
            (8, 9),
            (9, 10),
            (10, 11),
            (11, 12),
            (12, 13),
            (13, 14),
            (14, 15),
            (15, 4),
            (0, 4),
            (15, 16),
            (16, 17),
            (17, 12),
            (11, 1),
            (10, 2),
            (18, 19),
            (19, 20),
            (20, 21),
            (21, 18),
            (9, 22),
            (22, 23),
            (23, 6),
            (5, 3),
            (24, 7),
            (23, 24, circle_curve(frame((222.5, -612.8834964, 33.6900621), z_axis=(-1.0, 0.0, 0.0), x_axis=(0.0, 1.0, 0.0)), 32.6380788)),
            (25, 22, circle_curve(frame((-222.5, -612.8834964, 33.6900621), z_axis=(1.0, 0.0, 0.0), x_axis=(0.0, 1.0, 0.0)), 32.6380788)),
            (8, 25),
            (25, 24),
            (26, 27),
            (27, 17),
            (16, 28),
            (28, 29),
            (29, 30),
            (30, 31),
            (31, 26),
            (26, 14),
            (13, 27),
            (32, 33),
            (33, 34),
            (34, 35),
            (35, 32),
            (35, 30),
            (29, 32),
            (34, 31),
            (33, 28),
            (18, 36, circle_curve(frame((-292.5, -640.2074562, 891.0), z_axis=(0.0, 0.0, 1.0), x_axis=(1.0, 0.0, 0.0)), 20.0)),
            (36, 19, circle_curve(frame((-292.5, -640.2074562, 891.0), z_axis=(0.0, 0.0, 1.0), x_axis=(1.0, 0.0, 0.0)), 20.0)),
            (20, 37, circle_curve(frame((-292.5, -640.2074562, 1234.0), z_axis=(0.0, 0.0, -1.0), x_axis=(1.0, 0.0, 0.0)), 20.0)),
            (37, 21, circle_curve(frame((-292.5, -640.2074562, 1234.0), z_axis=(0.0, 0.0, -1.0), x_axis=(1.0, 0.0, 0.0)), 20.0)),
            (37, 36),
        ],
        [
            plane_surface(frame((-292.5, -674.5, 1854.0), z_axis=(0.0, -1.0, 0.0), x_axis=(-1.0, 0.0, 0.0))),
            plane_surface(frame((-292.5, -603.5, 1854.0), z_axis=(0.0, 1.0, 0.0), x_axis=(1.0, 0.0, 0.0))),
            plane_surface(frame((292.5, -674.5, 1854.0), z_axis=(0.0, 0.0, 1.0), x_axis=(0.0, 1.0, 0.0))),
            plane_surface(frame((-292.5, -674.5, 1854.0), z_axis=(-1.0, 0.0, 0.0), x_axis=(0.0, 1.0, 0.0))),
            plane_surface(frame((-292.5, -674.5, 36.0), z_axis=(0.0, 0.0, -1.0), x_axis=(0.0, 1.0, 0.0))),
            plane_surface(frame((292.5, -674.5, 36.0), z_axis=(1.0, 0.0, 0.0), x_axis=(0.0, 1.0, 0.0))),
            plane_surface(frame((222.5, -580.2454176, 33.6900621), z_axis=(-1.0, 0.0, 0.0), x_axis=(0.0, 0.0, 1.0))),
            plane_surface(frame((-222.5, -580.2454176, 33.6900621), z_axis=(1.0, 0.0, 0.0), x_axis=(0.0, 0.0, -1.0))),
            revolved_surface(polyline([(222.5, -580.2454176, 33.6900621), (-222.5, -580.2454176, 33.6900621)]), (-222.5, -612.8834964, 33.6900621), (1.0, 0.0, 0.0)),
            plane_surface(frame((222.5, -603.5, 66.0), z_axis=(0.0, 0.0, -1.0), x_axis=(-1.0, 0.0, 0.0))),
            plane_surface(frame((285.5, -614.5, 1867.7474822), z_axis=(0.0, 1.0, 0.0), x_axis=(-1.0, 0.0, 0.0))),
            plane_surface(frame((285.5, -614.5, 1797.0), z_axis=(0.0, 0.0, 1.0), x_axis=(-1.0, 0.0, 0.0))),
            plane_surface(frame((192.5, -660.3426016, 1848.5014777), z_axis=(0.0, 1.0, 0.0), x_axis=(0.0, 0.0, -1.0))),
            plane_surface(frame((-285.5, -603.5, 1797.0), z_axis=(1.0, 0.0, 0.0), x_axis=(0.0, 0.0, -1.0))),
            plane_surface(frame((192.5, -660.3426016, 1848.5014777), z_axis=(1.0, 0.0, 0.0), x_axis=(0.0, 1.0, 0.0))),
            plane_surface(frame((192.5, -660.3426016, 1800.5014777), z_axis=(0.0, 0.0, 1.0), x_axis=(0.0, 1.0, 0.0))),
            plane_surface(frame((285.5, -660.3426016, 1800.5014777), z_axis=(-1.0, 0.0, 0.0), x_axis=(0.0, 1.0, 0.0))),
            plane_surface(frame((285.5, -660.3426016, 1848.5014777), z_axis=(0.0, 0.0, -1.0), x_axis=(0.0, 1.0, 0.0))),
            plane_surface(frame((-272.5, -640.2074562, 891.0), z_axis=(0.0, 0.0, 1.0), x_axis=(0.0, -1.0, 0.0))),
            plane_surface(frame((-272.5, -640.2074562, 1234.0), z_axis=(0.0, 0.0, -1.0), x_axis=(0.0, 1.0, 0.0))),
            revolved_surface(polyline([(-272.5, -640.2074562, 1234.0), (-272.5, -640.2074562, 891.0)]), (-292.5, -640.2074562, 891.0), (0.0, 0.0, 1.0)),
        ],
        [
            (0, [[1, 2, 3, 4]]),
            (1, [[5, 6, 7, 8, 9, 10, 11, 12, 13, 14, 15, 16]]),
            (2, [[-1, 17, -16, 18, 19, 20, -12, 21]]),
            (3, [[-2, -21, -11, 22], [23, 24, 25, 26]]),
            (4, [[-3, -22, -10, 27, 28, 29, -6, 30]]),
            (5, [[-4, -30, -5, -17]]),
            (6, [[31, -7, -29, 32]]),
            (7, [[33, -27, -9, 34]]),
            (8, [[-32, -28, -33, 35]]),
            (9, [[-31, -35, -34, -8]]),
            (10, [[36, 37, -19, 38, 39, 40, 41, 42]]),
            (11, [[43, -14, 44, -36]]),
            (12, [[45, 46, 47, 48]]),
            (13, [[-44, -13, -20, -37]]),
            (14, [[-48, 49, -40, 50]]),
            (15, [[-47, 51, -41, -49]]),
            (16, [[-46, 52, -38, -18, -15, -43, -42, -51]]),
            (17, [[-45, -50, -39, -52]]),
            (18, [[53, 54, -23]]),
            (19, [[55, 56, -25]]),
            (20, [[57, -53, -26, -56]]),
            (20, [[-57, -55, -24, -54]]),
        ],
    ),
    ])


if __name__ == "__main__":
    model = new_model("IFC4")
    model_context = context("Model", 3, world=origin())
    ifc_project = project(units=[si_unit("LENGTHUNIT", "METRE", prefix="MILLI")], contexts=[model_context])
    site = spatial("IfcSite", under=ifc_project)
    building = spatial("IfcBuilding", under=site)
    placement = place(None, origin())
    specialty_equipment_shape = specialty_equipment_c88ea4fe(model_context)
    element("IfcBuildingElementProxy", 1, Name="Specialty Equipment", at=placement, inside=building, context=model_context, shape_type="MappedRepresentation", body=[
        mapped(specialty_equipment_shape, transform((0.0, 0.0, 0.0), x_axis=(1.0, 0.0, 0.0), y_axis=(0.0, 1.0, 0.0), z_axis=(0.0, 0.0, 1.0))),
    ])
    save(model, "model.ifc")
